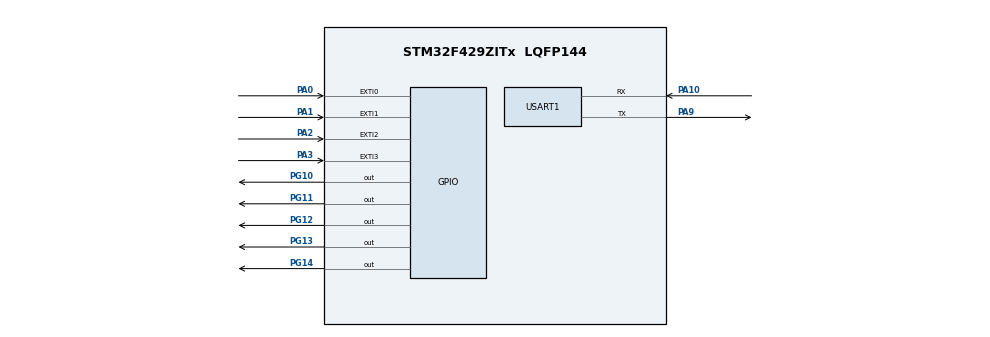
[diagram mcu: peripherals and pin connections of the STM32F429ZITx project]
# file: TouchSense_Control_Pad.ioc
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FREERTOS.INCLUDE_xEventGroupSetBitFromISR=1
FREERTOS.INCLUDE_xTimerPendFunctionCall=1
FREERTOS.Mutexes01=myMutex01,Dynamic,NULL,Available
FREERTOS.Tasks01=defaultTask,0,128,StartDefaultTask,Default,NULL,Dynamic,NULL,NULL
FREERTOS.Timers01=myTimer01,Callback01,osTimerPeriodic,Default,NULL,Dynamic,NULL
FREERTOS.configGENERATE_RUN_TIME_STATS=1
FREERTOS.configUSE_NEWLIB_REENTRANT=1
FREERTOS.configUSE_TIMERS=1
FREERTOS.configUSE_TRACE_FACILITY=1
Mcu.Family=STM32F4
Mcu.Name=STM32F429ZITx
Mcu.Package=LQFP144
NVIC.EXTI0_IRQn=true\:5\:0\:false\:false\:true\:false\:true\:true\:true
NVIC.EXTI1_IRQn=true\:5\:0\:false\:false\:true\:false\:true\:true\:true
NVIC.EXTI2_IRQn=true\:5\:0\:false\:false\:true\:false\:true\:true\:true
NVIC.EXTI3_IRQn=true\:5\:0\:false\:false\:true\:false\:true\:true\:true
NVIC.PriorityGroup=NVIC_PRIORITYGROUP_4
NVIC.USART1_IRQn=true\:5\:0\:false\:false\:true\:true\:true\:true\:true
PA0/WKUP.GPIO_ModeDefaultEXTI=GPIO_MODE_IT_RISING
PA0/WKUP.GPIO_PuPd=GPIO_PULLDOWN
PA0/WKUP.Signal=GPXTI0
PA1.GPIO_ModeDefaultEXTI=GPIO_MODE_IT_RISING
PA1.GPIO_PuPd=GPIO_PULLDOWN
PA1.Signal=GPXTI1
PA10.Mode=Asynchronous
PA10.Signal=USART1_RX
PA2.GPIO_ModeDefaultEXTI=GPIO_MODE_IT_RISING
PA2.GPIO_PuPd=GPIO_PULLDOWN
PA2.Signal=GPXTI2
PA3.GPIO_ModeDefaultEXTI=GPIO_MODE_IT_RISING
PA3.GPIO_PuPd=GPIO_PULLDOWN
PA3.Signal=GPXTI3
PA9.Mode=Asynchronous
PA9.Signal=USART1_TX
PG10.Signal=GPIO_Output
PG11.Signal=GPIO_Output
PG12.Signal=GPIO_Output
PG13.Signal=GPIO_Output
PG14.Signal=GPIO_Output
ProjectManager.HeapSize=0x200
ProjectManager.StackSize=0x400
ProjectManager.TargetToolchain=STM32CubeIDE
RCC.AHBFreq_Value=16000000
RCC.APB1Freq_Value=16000000
RCC.APB2Freq_Value=16000000
RCC.CortexFreq_Value=16000000
RCC.HSE_VALUE=25000000
RCC.HSI_VALUE=16000000
RCC.LSE_VALUE=32768
RCC.SYSCLKFreq_VALUE=16000000
RCC.VCOOutputFreq_Value=192000000
USART1.VirtualMode=VM_ASYNC
VP_FREERTOS_VS_CMSIS_V1.Mode=CMSIS_V1
board=custom

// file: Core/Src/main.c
/* USER CODE BEGIN Header */
/**
 ******************************************************************************
 * @file           : main.c
 * @brief          : Main program body
 ******************************************************************************
 * @attention
 *
 * Copyright (c) 2026 STMicroelectronics.
 * All rights reserved.
 *
 * This software is licensed under terms that can be found in the LICENSE file
 * in the root directory of this software component.
 * If no LICENSE file comes with this software, it is provided AS-IS.
 *
 ******************************************************************************
 */
/* USER CODE END Header */
#include "main.h"
#include "cmsis_os.h"

/* USER CODE BEGIN Includes */
#include<stdio.h>
#include<string.h>
#include "task.h"

/*======================= MACROS =======================*/
#define EMER_LED      GPIO_PIN_14
#define TASK1_LED     GPIO_PIN_10
#define TASK2_LED     GPIO_PIN_11
#define TASK3_LED     GPIO_PIN_12

#define EMER	        0x01
#define TASK1			0x02
#define TASK2 			0x04
#define TASK3 			0x08

#define TLS_INDEX 0 // Index for the thread-local storage pointer

/* USER CODE END Includes */

UART_HandleTypeDef huart1;

//osThreadId defaultTaskHandle;
//osTimerId myTimer01Handle;
//osMutexId myMutex01Handle;

void SystemClock_Config(void);
static void MX_GPIO_Init(void);
static void MX_USART1_UART_Init(void);
//void StartDefaultTask(void const * argument);
//void Callback01(void const * argument);

/* USER CODE BEGIN 0 */

/*================ TASK PROTOTYPES ==================*/
void Task1(void *arg);
void Task2(void *arg);
void Task3(void *arg);
void Emergency_Task(void *arg);
void Control_Task(void *arg);
void UART_Task(void *arg);
void Toggle_LED( uint16_t pin);
void Timer_Task1(TimerHandle_t xTimer); //To print health for every 15sec
void Timer_Task2(TimerHandle_t xTimer); //To overcome bouncing effect

/* =============== PRINTF ============================*/
//To use printf()
int _write(int file, char *ptr, int len) {
	HAL_UART_Transmit(&huart1, (uint8_t*) ptr, (uint16_t) len, HAL_MAX_DELAY);
	return len;
}

/*==================== HANDLES =======================*/
SemaphoreHandle_t LED_Mutex;
SemaphoreHandle_t UART_Mutex;

TimerHandle_t TimerHandle1, TimerHandle2;
EventGroupHandle_t EventGroupHandle;
TaskHandle_t Emer_Handle, Task1_Handle, Task2_Handle, Task3_Handle,
		Control_Handle, UART_Handle;

uint16_t PRESSED_Pin;
uint8_t rx_char;
uint8_t status[50];
uint8_t i = 0;
/*============== COMMON LED TOGGLE FUNCTION ===========*/
void Toggle_LED( uint16_t pin) {
	xSemaphoreTake(LED_Mutex, portMAX_DELAY);
	HAL_GPIO_TogglePin(GPIOG, pin);
	xSemaphoreGive(LED_Mutex);
}
/* USER CODE END 0 */

int main(void) {

	/* MCU Configuration--------------------------------------------------------*/

	/* Reset of all peripherals, Initializes the Flash interface and the Systick. */
	HAL_Init();

	/* Configure the system clock */
	SystemClock_Config();

	/* Initialize all configured peripherals */
	MX_GPIO_Init();
	MX_USART1_UART_Init();
	/* USER CODE BEGIN 2 */

	/*================ MUTEX CREATION =====================*/
	LED_Mutex = xSemaphoreCreateMutex(); //Mutex for Common Toggle LED function
	UART_Mutex = xSemaphoreCreateMutex(); //Mutex for UART

	/*=============== SOFTWARE TIMER CREATION =============*/
	TimerHandle1 = xTimerCreate("Timerpc", pdMS_TO_TICKS(15000), pdTRUE, 0,
			Timer_Task1);
	TimerHandle2 = xTimerCreate("Timer2_pc", pdMS_TO_TICKS(50), pdFALSE, 0,
			Timer_Task2);

	/*================= TASK CREATIONS ====================*/
	xTaskCreate(Emergency_Task, "Eme_task_pc", 128, NULL, 2, &Emer_Handle);
	xTaskCreate(Task1, "Task1_pc", 128, NULL, 1, &Task1_Handle);
	xTaskCreate(Task2, "Task2_pc", 128, NULL, 1, &Task2_Handle);
	xTaskCreate(Task3, "Task3_pc", 128, NULL, 1, &Task3_Handle);
	xTaskCreate(Control_Task, "Control_pc", 128, NULL, 2, &Control_Handle);
	xTaskCreate(UART_Task, "UART_pc", 128, NULL, 0, &UART_Handle);

	/*================EVENT GROUP CREATION============================*/
	EventGroupHandle = xEventGroupCreate();

	//Suspending all the tasks initially
	vTaskSuspend(Emer_Handle);
	vTaskSuspend(Task1_Handle);
	vTaskSuspend(Task2_Handle);
	vTaskSuspend(Task3_Handle);

	//Start the software timer
	xTimerStart(TimerHandle1, 0);

	//receiving one character from UART
	HAL_UART_Receive_IT(&huart1, &rx_char, 1);

	//Start the scheduler
	vTaskStartScheduler();

	/* USER CODE END 2 */

	/* Create the mutex(es) */
	/* definition and creation of myMutex01 */
//  osMutexDef(myMutex01);
//  myMutex01Handle = osMutexCreate(osMutex(myMutex01));

	/* Create the timer(s) */
	/* definition and creation of myTimer01 */
//  osTimerDef(myTimer01, Callback01);
//  myTimer01Handle = osTimerCreate(osTimer(myTimer01), osTimerPeriodic, NULL);

	/* Create the thread(s) */
	/* definition and creation of defaultTask */
//  osThreadDef(defaultTask, StartDefaultTask, osPriorityNormal, 0, 128);
//  defaultTaskHandle = osThreadCreate(osThread(defaultTask), NULL);

	/* Start scheduler */
	//osKernelStart();
	/* We should never get here as control is now taken by the scheduler */

	/* Infinite loop */
	while (1) {

	}
}

void SystemClock_Config(void) {
	RCC_OscInitTypeDef RCC_OscInitStruct = { 0 };
	RCC_ClkInitTypeDef RCC_ClkInitStruct = { 0 };

	/** Configure the main internal regulator output voltage
	 */
	__HAL_RCC_PWR_CLK_ENABLE();
	__HAL_PWR_VOLTAGESCALING_CONFIG(PWR_REGULATOR_VOLTAGE_SCALE1);

	/** Initializes the RCC Oscillators according to the specified parameters
	 * in the RCC_OscInitTypeDef structure.
	 */
	RCC_OscInitStruct.OscillatorType = RCC_OSCILLATORTYPE_HSI;
	RCC_OscInitStruct.HSIState = RCC_HSI_ON;
	RCC_OscInitStruct.HSICalibrationValue = RCC_HSICALIBRATION_DEFAULT;
	RCC_OscInitStruct.PLL.PLLState = RCC_PLL_ON;
	RCC_OscInitStruct.PLL.PLLSource = RCC_PLLSOURCE_HSI;
	RCC_OscInitStruct.PLL.PLLM = 8;
	RCC_OscInitStruct.PLL.PLLN = 180;
	RCC_OscInitStruct.PLL.PLLP = RCC_PLLP_DIV2;
	RCC_OscInitStruct.PLL.PLLQ = 4;
	if (HAL_RCC_OscConfig(&RCC_OscInitStruct) != HAL_OK) {
		Error_Handler();
	}

	/** Activate the Over-Drive mode
	 */
	if (HAL_PWREx_EnableOverDrive() != HAL_OK) {
		Error_Handler();
	}

	/** Initializes the CPU, AHB and APB buses clocks
	 */
	RCC_ClkInitStruct.ClockType = RCC_CLOCKTYPE_HCLK | RCC_CLOCKTYPE_SYSCLK
			| RCC_CLOCKTYPE_PCLK1 | RCC_CLOCKTYPE_PCLK2;
	RCC_ClkInitStruct.SYSCLKSource = RCC_SYSCLKSOURCE_PLLCLK;
	RCC_ClkInitStruct.AHBCLKDivider = RCC_SYSCLK_DIV1;
	RCC_ClkInitStruct.APB1CLKDivider = RCC_HCLK_DIV4;
	RCC_ClkInitStruct.APB2CLKDivider = RCC_HCLK_DIV2;

	if (HAL_RCC_ClockConfig(&RCC_ClkInitStruct, FLASH_LATENCY_5) != HAL_OK) {
		Error_Handler();
	}
}

static void MX_USART1_UART_Init(void) {

	huart1.Instance = USART1;
	huart1.Init.BaudRate = 115200;
	huart1.Init.WordLength = UART_WORDLENGTH_8B;
	huart1.Init.StopBits = UART_STOPBITS_1;
	huart1.Init.Parity = UART_PARITY_NONE;
	huart1.Init.Mode = UART_MODE_TX_RX;
	huart1.Init.HwFlowCtl = UART_HWCONTROL_NONE;
	huart1.Init.OverSampling = UART_OVERSAMPLING_16;
	if (HAL_UART_Init(&huart1) != HAL_OK) {
		Error_Handler();
	}

}

static void MX_GPIO_Init(void) {
	GPIO_InitTypeDef GPIO_InitStruct = { 0 };

	/* GPIO Ports Clock Enable */
	__HAL_RCC_GPIOA_CLK_ENABLE();
	__HAL_RCC_GPIOG_CLK_ENABLE();

	/*Configure GPIO pin Output Level */
	HAL_GPIO_WritePin(GPIOG,
	GPIO_PIN_10 | GPIO_PIN_11 | GPIO_PIN_12 | GPIO_PIN_13 | GPIO_PIN_14,
			GPIO_PIN_RESET);

	/*Configure GPIO pins : PA0 PA1 PA2 PA3 */
	GPIO_InitStruct.Pin = GPIO_PIN_0 | GPIO_PIN_1 | GPIO_PIN_2 | GPIO_PIN_3;
	GPIO_InitStruct.Mode = GPIO_MODE_IT_RISING;
	GPIO_InitStruct.Pull = GPIO_PULLDOWN;
	HAL_GPIO_Init(GPIOA, &GPIO_InitStruct);

	/*Configure GPIO pins : PG10 PG11 PG12 PG13
	 PG14 */
	GPIO_InitStruct.Pin = GPIO_PIN_10 | GPIO_PIN_11 | GPIO_PIN_12 | GPIO_PIN_13
			| GPIO_PIN_14;
	GPIO_InitStruct.Mode = GPIO_MODE_OUTPUT_PP;
	GPIO_InitStruct.Pull = GPIO_NOPULL;
	GPIO_InitStruct.Speed = GPIO_SPEED_FREQ_LOW;
	HAL_GPIO_Init(GPIOG, &GPIO_InitStruct);

	/* EXTI interrupt init*/
	HAL_NVIC_SetPriority(EXTI0_IRQn, 5, 0);
	HAL_NVIC_EnableIRQ(EXTI0_IRQn);

	HAL_NVIC_SetPriority(EXTI1_IRQn, 5, 0);
	HAL_NVIC_EnableIRQ(EXTI1_IRQn);

	HAL_NVIC_SetPriority(EXTI2_IRQn, 5, 0);
	HAL_NVIC_EnableIRQ(EXTI2_IRQn);

	HAL_NVIC_SetPriority(EXTI3_IRQn, 5, 0);
	HAL_NVIC_EnableIRQ(EXTI3_IRQn);

}

/* USER CODE BEGIN 4 */
uint8_t bit;
uint32_t count=0;
uint32_t *cnt;
//CONTROLLER TASK
void Control_Task(void *arg) {
	vTaskSetThreadLocalStoragePointer(NULL, TLS_INDEX, (void *)&count);
	for (;;) {
		bit = xEventGroupWaitBits(EventGroupHandle, EMER | TASK1 | TASK2 | TASK3,
		pdTRUE, pdFALSE, portMAX_DELAY); // read the bit value and clear
		// Set thread-local storage for the current task
		cnt = (uint32_t *)pvTaskGetThreadLocalStoragePointer(NULL, TLS_INDEX);
		(*cnt)++;
		//vTaskSetThreadLocalStoragePointer(NULL, TLS_INDEX, (void *)cnt);

//		cnt = pvTaskGetThreadLocalStoragePointer(NULL, TLS_INDEX);
//		printf("No of times Events Changed: %ld\r\n", *cnt);

		switch (bit) {
		case EMER:	//If Emergency bit is set resume it and suspend remaining.
			//count++;
			vTaskResume(Emer_Handle);
			vTaskSuspend(Task1_Handle);
			vTaskSuspend(Task2_Handle);
			vTaskSuspend(Task3_Handle);
			break;

		case TASK1:		//If Task1 bit is set resume it and suspend remaining.
			//count++;
			vTaskResume(Task1_Handle);
			vTaskSuspend(Emer_Handle);
			vTaskSuspend(Task2_Handle);
			vTaskSuspend(Task3_Handle);
			break;

		case TASK2:		//If Task2 bit is set resume it and suspend remaining.
			//count++;
			vTaskResume(Task2_Handle);
			vTaskSuspend(Emer_Handle);
			vTaskSuspend(Task1_Handle);
			vTaskSuspend(Task3_Handle);
			break;

		case TASK3:		//If task3 bit is set resume it and suspend remaining.
			//count++;
			vTaskResume(Task3_Handle);
			vTaskSuspend(Emer_Handle);
			vTaskSuspend(Task2_Handle);
			vTaskSuspend(Task1_Handle);
			break;

		}
	}
}

//call back function when interrupt is given
//For deboucing effect, we are using a timer and starting the one shot timer in interrupt
void HAL_GPIO_EXTI_Callback(uint16_t GPIO_Pin) {
	PRESSED_Pin=GPIO_Pin;
	BaseType_t xHigherPriorityTaskWoken = pdFALSE;
	xTimerStartFromISR(TimerHandle2, &xHigherPriorityTaskWoken);
	portYIELD_FROM_ISR(xHigherPriorityTaskWoken);
}

//void Timer_Task2(TimerHandle_t xTimer) {
//	if (PRESSED_Pin==GPIO_PIN_0) {
//		xEventGroupSetBits(EventGroupHandle, EMER);
//		count++;
//	} else if (PRESSED_Pin==GPIO_PIN_1) {
//		xEventGroupSetBits(EventGroupHandle, TASK1);
//		count++;
//	} else if (PRESSED_Pin==GPIO_PIN_2) {
//		xEventGroupSetBits(EventGroupHandle, TASK2);
//		count++;
//	} else if (PRESSED_Pin==GPIO_PIN_3) {
//		xEventGroupSetBits(EventGroupHandle, TASK3);
//		count++;
//	}
//}

void Timer_Task2(TimerHandle_t xTimer) {
	if ((HAL_GPIO_ReadPin(GPIOA, GPIO_PIN_0)) == 1) {
		xEventGroupSetBits(EventGroupHandle, EMER);
		//count++;
	} else if ((HAL_GPIO_ReadPin(GPIOA, GPIO_PIN_1)) == 1) {
		xEventGroupSetBits(EventGroupHandle, TASK1);
		//count++;
	} else if ((HAL_GPIO_ReadPin(GPIOA, GPIO_PIN_2)) == 1) {
		xEventGroupSetBits(EventGroupHandle, TASK2);
		//count++;
	} else if ((HAL_GPIO_ReadPin(GPIOA, GPIO_PIN_3)) == 1) {
		xEventGroupSetBits(EventGroupHandle, TASK3);
		//count++;
	}
}

void HAL_UART_RxCpltCallback(UART_HandleTypeDef *huart) {
	if (huart->Instance == USART1) {
		status[i] = rx_char;
		i++;

		HAL_UART_Receive_IT(&huart1, &rx_char, 1);  // Restart UART interrupt

		if ((i == 14) || ( (i == 9)) &&(!strncmp((char*) status, "STATUS?\r\n", 9))) {
			BaseType_t xHigherPriorityTaskWoken = pdFALSE;
			vTaskNotifyGiveFromISR(UART_Handle, &xHigherPriorityTaskWoken); // Notify UART task that new data arrived
			portYIELD_FROM_ISR(xHigherPriorityTaskWoken);
		}
	}
}

//Emergency task
void Emergency_Task(void *arg) {
	for (;;) {
		Toggle_LED(EMER_LED);
		vTaskDelay(pdMS_TO_TICKS(250));
	}
}

//Task1 - Toggle LED for 500ms
void Task1(void *arg) {
	for (;;) {
		Toggle_LED(TASK1_LED);
		vTaskDelay(pdMS_TO_TICKS(500));

	}
}
//Task2 - Toggle LED for 100ms
void Task2(void *arg) {
	for (;;) {
		Toggle_LED(TASK2_LED);
		vTaskDelay(pdMS_TO_TICKS(1000));

	}
}
//Task3 - Toggle LED for 150ms
void Task3(void *arg) {
	for (;;) {
		Toggle_LED(TASK3_LED);
		vTaskDelay(pdMS_TO_TICKS(1500));

	}
}

//Timer task to print the number of event changes for every 15 sec
void Timer_Task1(TimerHandle_t xTimer) {
	i = 0;
	cnt = pvTaskGetThreadLocalStoragePointer(Control_Handle, TLS_INDEX);

	//print how many times event changed
	xSemaphoreTake(UART_Mutex, portMAX_DELAY);
	printf("No of times Events Changed: %ld\r\n", *cnt);
	xSemaphoreGive(UART_Mutex);
}

uint8_t health[500]; //health buffer

//UART task
void UART_Task(void *arg) {
	for (;;) {
		ulTaskNotifyTake(pdTRUE, portMAX_DELAY);
		if ((!strncmp((char*) status, "STATUS?\r\n", 9))) {
			vTaskList(health); //Lists all the tasks
			xSemaphoreTake(UART_Mutex, portMAX_DELAY);
			printf("%s\r\n", health);
			xSemaphoreGive(UART_Mutex);
		}
		//user changing to emergency mode
		else if (!(strncmp((char*) status, "SET_MODE=EMERG", 14))) {
			xEventGroupSetBits(EventGroupHandle, EMER);
			//count++;

		}
		//user changing to task1 mode
		else if (!(strncmp((char*) status, "SET_MODE=TASK1", 14))) {
			xEventGroupSetBits(EventGroupHandle, TASK1);
			//count++;

		}
		//user changing to task2 mode
		else if (!(strncmp((char*) status, "SET_MODE=TASK2", 14))) {
			xEventGroupSetBits(EventGroupHandle, TASK2);
			//count++;

		}
		//user changing to task3 mode
		else if (!(strncmp((char*) status, "SET_MODE=TASK3", 14))) {
			xEventGroupSetBits(EventGroupHandle, TASK3);
			//count++;
		}
	}
}

/* USER CODE END 4 */

//void StartDefaultTask(void const * argument)
//{
/* USER CODE BEGIN 5 */
/* Infinite loop */
//  for(;;)
//  {
//    osDelay(1);
//  }
/* USER CODE END 5 */
//}
/* Callback01 function */
//void Callback01(void const * argument)
//{
//}
void HAL_TIM_PeriodElapsedCallback(DMA_HandleTypeDef *htim) {
	if (htim->Instance == TIM1) {
		HAL_IncTick();
	}
}

void Error_Handler(void) {
	__disable_irq();
	while (1) {
	}
}
